VERSION 5.7 ;
BUSBITCHARS "[]" ;
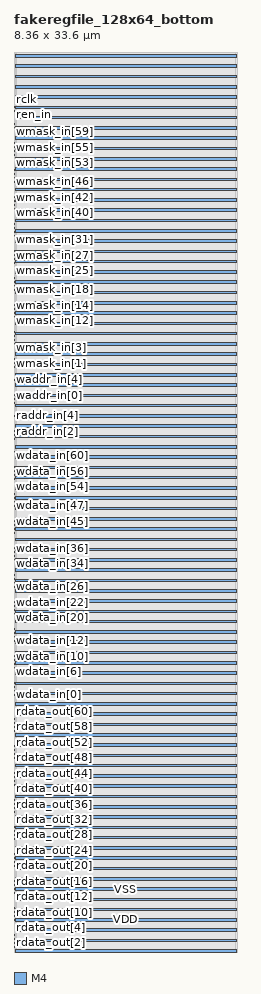
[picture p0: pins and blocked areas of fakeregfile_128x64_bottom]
MACRO fakeregfile_128x64_bottom
  FOREIGN fakeregfile_128x64_bottom 0 0 ;
  SYMMETRY X Y R90 ;
  SIZE 8.360 BY 33.600 ;
  CLASS BLOCK ;
  PIN rdata_out[0]
    DIRECTION OUTPUT ;
    USE SIGNAL ;
    SHAPE ABUTMENT ;
    PORT
      LAYER M4 ;
      RECT 0.000 0.039 0.024 0.063 ;
    END
  END rdata_out[0]
  PIN rdata_out[1]
    DIRECTION OUTPUT ;
    USE SIGNAL ;
    SHAPE ABUTMENT ;
    PORT
      LAYER M4 ;
      RECT 0.000 0.183 0.024 0.207 ;
    END
  END rdata_out[1]
  PIN rdata_out[2]
    DIRECTION OUTPUT ;
    USE SIGNAL ;
    SHAPE ABUTMENT ;
    PORT
      LAYER M4 ;
      RECT 0.000 0.327 0.024 0.351 ;
    END
  END rdata_out[2]
  PIN rdata_out[3]
    DIRECTION OUTPUT ;
    USE SIGNAL ;
    SHAPE ABUTMENT ;
    PORT
      LAYER M4 ;
      RECT 0.000 0.471 0.024 0.495 ;
    END
  END rdata_out[3]
  PIN rdata_out[4]
    DIRECTION OUTPUT ;
    USE SIGNAL ;
    SHAPE ABUTMENT ;
    PORT
      LAYER M4 ;
      RECT 0.000 0.615 0.024 0.639 ;
    END
  END rdata_out[4]
  PIN rdata_out[5]
    DIRECTION OUTPUT ;
    USE SIGNAL ;
    SHAPE ABUTMENT ;
    PORT
      LAYER M4 ;
      RECT 0.000 0.759 0.024 0.783 ;
    END
  END rdata_out[5]
  PIN rdata_out[6]
    DIRECTION OUTPUT ;
    USE SIGNAL ;
    SHAPE ABUTMENT ;
    PORT
      LAYER M4 ;
      RECT 0.000 0.903 0.024 0.927 ;
    END
  END rdata_out[6]
  PIN rdata_out[7]
    DIRECTION OUTPUT ;
    USE SIGNAL ;
    SHAPE ABUTMENT ;
    PORT
      LAYER M4 ;
      RECT 0.000 1.047 0.024 1.071 ;
    END
  END rdata_out[7]
  PIN rdata_out[8]
    DIRECTION OUTPUT ;
    USE SIGNAL ;
    SHAPE ABUTMENT ;
    PORT
      LAYER M4 ;
      RECT 0.000 1.191 0.024 1.215 ;
    END
  END rdata_out[8]
  PIN rdata_out[9]
    DIRECTION OUTPUT ;
    USE SIGNAL ;
    SHAPE ABUTMENT ;
    PORT
      LAYER M4 ;
      RECT 0.000 1.335 0.024 1.359 ;
    END
  END rdata_out[9]
  PIN rdata_out[10]
    DIRECTION OUTPUT ;
    USE SIGNAL ;
    SHAPE ABUTMENT ;
    PORT
      LAYER M4 ;
      RECT 0.000 1.479 0.024 1.503 ;
    END
  END rdata_out[10]
  PIN rdata_out[11]
    DIRECTION OUTPUT ;
    USE SIGNAL ;
    SHAPE ABUTMENT ;
    PORT
      LAYER M4 ;
      RECT 0.000 1.623 0.024 1.647 ;
    END
  END rdata_out[11]
  PIN rdata_out[12]
    DIRECTION OUTPUT ;
    USE SIGNAL ;
    SHAPE ABUTMENT ;
    PORT
      LAYER M4 ;
      RECT 0.000 1.767 0.024 1.791 ;
    END
  END rdata_out[12]
  PIN rdata_out[13]
    DIRECTION OUTPUT ;
    USE SIGNAL ;
    SHAPE ABUTMENT ;
    PORT
      LAYER M4 ;
      RECT 0.000 1.911 0.024 1.935 ;
    END
  END rdata_out[13]
  PIN rdata_out[14]
    DIRECTION OUTPUT ;
    USE SIGNAL ;
    SHAPE ABUTMENT ;
    PORT
      LAYER M4 ;
      RECT 0.000 2.055 0.024 2.079 ;
    END
  END rdata_out[14]
  PIN rdata_out[15]
    DIRECTION OUTPUT ;
    USE SIGNAL ;
    SHAPE ABUTMENT ;
    PORT
      LAYER M4 ;
      RECT 0.000 2.199 0.024 2.223 ;
    END
  END rdata_out[15]
  PIN rdata_out[16]
    DIRECTION OUTPUT ;
    USE SIGNAL ;
    SHAPE ABUTMENT ;
    PORT
      LAYER M4 ;
      RECT 0.000 2.343 0.024 2.367 ;
    END
  END rdata_out[16]
  PIN rdata_out[17]
    DIRECTION OUTPUT ;
    USE SIGNAL ;
    SHAPE ABUTMENT ;
    PORT
      LAYER M4 ;
      RECT 0.000 2.487 0.024 2.511 ;
    END
  END rdata_out[17]
  PIN rdata_out[18]
    DIRECTION OUTPUT ;
    USE SIGNAL ;
    SHAPE ABUTMENT ;
    PORT
      LAYER M4 ;
      RECT 0.000 2.631 0.024 2.655 ;
    END
  END rdata_out[18]
  PIN rdata_out[19]
    DIRECTION OUTPUT ;
    USE SIGNAL ;
    SHAPE ABUTMENT ;
    PORT
      LAYER M4 ;
      RECT 0.000 2.775 0.024 2.799 ;
    END
  END rdata_out[19]
  PIN rdata_out[20]
    DIRECTION OUTPUT ;
    USE SIGNAL ;
    SHAPE ABUTMENT ;
    PORT
      LAYER M4 ;
      RECT 0.000 2.919 0.024 2.943 ;
    END
  END rdata_out[20]
  PIN rdata_out[21]
    DIRECTION OUTPUT ;
    USE SIGNAL ;
    SHAPE ABUTMENT ;
    PORT
      LAYER M4 ;
      RECT 0.000 3.063 0.024 3.087 ;
    END
  END rdata_out[21]
  PIN rdata_out[22]
    DIRECTION OUTPUT ;
    USE SIGNAL ;
    SHAPE ABUTMENT ;
    PORT
      LAYER M4 ;
      RECT 0.000 3.207 0.024 3.231 ;
    END
  END rdata_out[22]
  PIN rdata_out[23]
    DIRECTION OUTPUT ;
    USE SIGNAL ;
    SHAPE ABUTMENT ;
    PORT
      LAYER M4 ;
      RECT 0.000 3.351 0.024 3.375 ;
    END
  END rdata_out[23]
  PIN rdata_out[24]
    DIRECTION OUTPUT ;
    USE SIGNAL ;
    SHAPE ABUTMENT ;
    PORT
      LAYER M4 ;
      RECT 0.000 3.495 0.024 3.519 ;
    END
  END rdata_out[24]
  PIN rdata_out[25]
    DIRECTION OUTPUT ;
    USE SIGNAL ;
    SHAPE ABUTMENT ;
    PORT
      LAYER M4 ;
      RECT 0.000 3.639 0.024 3.663 ;
    END
  END rdata_out[25]
  PIN rdata_out[26]
    DIRECTION OUTPUT ;
    USE SIGNAL ;
    SHAPE ABUTMENT ;
    PORT
      LAYER M4 ;
      RECT 0.000 3.783 0.024 3.807 ;
    END
  END rdata_out[26]
  PIN rdata_out[27]
    DIRECTION OUTPUT ;
    USE SIGNAL ;
    SHAPE ABUTMENT ;
    PORT
      LAYER M4 ;
      RECT 0.000 3.927 0.024 3.951 ;
    END
  END rdata_out[27]
  PIN rdata_out[28]
    DIRECTION OUTPUT ;
    USE SIGNAL ;
    SHAPE ABUTMENT ;
    PORT
      LAYER M4 ;
      RECT 0.000 4.071 0.024 4.095 ;
    END
  END rdata_out[28]
  PIN rdata_out[29]
    DIRECTION OUTPUT ;
    USE SIGNAL ;
    SHAPE ABUTMENT ;
    PORT
      LAYER M4 ;
      RECT 0.000 4.215 0.024 4.239 ;
    END
  END rdata_out[29]
  PIN rdata_out[30]
    DIRECTION OUTPUT ;
    USE SIGNAL ;
    SHAPE ABUTMENT ;
    PORT
      LAYER M4 ;
      RECT 0.000 4.359 0.024 4.383 ;
    END
  END rdata_out[30]
  PIN rdata_out[31]
    DIRECTION OUTPUT ;
    USE SIGNAL ;
    SHAPE ABUTMENT ;
    PORT
      LAYER M4 ;
      RECT 0.000 4.503 0.024 4.527 ;
    END
  END rdata_out[31]
  PIN rdata_out[32]
    DIRECTION OUTPUT ;
    USE SIGNAL ;
    SHAPE ABUTMENT ;
    PORT
      LAYER M4 ;
      RECT 0.000 4.647 0.024 4.671 ;
    END
  END rdata_out[32]
  PIN rdata_out[33]
    DIRECTION OUTPUT ;
    USE SIGNAL ;
    SHAPE ABUTMENT ;
    PORT
      LAYER M4 ;
      RECT 0.000 4.791 0.024 4.815 ;
    END
  END rdata_out[33]
  PIN rdata_out[34]
    DIRECTION OUTPUT ;
    USE SIGNAL ;
    SHAPE ABUTMENT ;
    PORT
      LAYER M4 ;
      RECT 0.000 4.935 0.024 4.959 ;
    END
  END rdata_out[34]
  PIN rdata_out[35]
    DIRECTION OUTPUT ;
    USE SIGNAL ;
    SHAPE ABUTMENT ;
    PORT
      LAYER M4 ;
      RECT 0.000 5.079 0.024 5.103 ;
    END
  END rdata_out[35]
  PIN rdata_out[36]
    DIRECTION OUTPUT ;
    USE SIGNAL ;
    SHAPE ABUTMENT ;
    PORT
      LAYER M4 ;
      RECT 0.000 5.223 0.024 5.247 ;
    END
  END rdata_out[36]
  PIN rdata_out[37]
    DIRECTION OUTPUT ;
    USE SIGNAL ;
    SHAPE ABUTMENT ;
    PORT
      LAYER M4 ;
      RECT 0.000 5.367 0.024 5.391 ;
    END
  END rdata_out[37]
  PIN rdata_out[38]
    DIRECTION OUTPUT ;
    USE SIGNAL ;
    SHAPE ABUTMENT ;
    PORT
      LAYER M4 ;
      RECT 0.000 5.511 0.024 5.535 ;
    END
  END rdata_out[38]
  PIN rdata_out[39]
    DIRECTION OUTPUT ;
    USE SIGNAL ;
    SHAPE ABUTMENT ;
    PORT
      LAYER M4 ;
      RECT 0.000 5.655 0.024 5.679 ;
    END
  END rdata_out[39]
  PIN rdata_out[40]
    DIRECTION OUTPUT ;
    USE SIGNAL ;
    SHAPE ABUTMENT ;
    PORT
      LAYER M4 ;
      RECT 0.000 5.799 0.024 5.823 ;
    END
  END rdata_out[40]
  PIN rdata_out[41]
    DIRECTION OUTPUT ;
    USE SIGNAL ;
    SHAPE ABUTMENT ;
    PORT
      LAYER M4 ;
      RECT 0.000 5.943 0.024 5.967 ;
    END
  END rdata_out[41]
  PIN rdata_out[42]
    DIRECTION OUTPUT ;
    USE SIGNAL ;
    SHAPE ABUTMENT ;
    PORT
      LAYER M4 ;
      RECT 0.000 6.087 0.024 6.111 ;
    END
  END rdata_out[42]
  PIN rdata_out[43]
    DIRECTION OUTPUT ;
    USE SIGNAL ;
    SHAPE ABUTMENT ;
    PORT
      LAYER M4 ;
      RECT 0.000 6.231 0.024 6.255 ;
    END
  END rdata_out[43]
  PIN rdata_out[44]
    DIRECTION OUTPUT ;
    USE SIGNAL ;
    SHAPE ABUTMENT ;
    PORT
      LAYER M4 ;
      RECT 0.000 6.375 0.024 6.399 ;
    END
  END rdata_out[44]
  PIN rdata_out[45]
    DIRECTION OUTPUT ;
    USE SIGNAL ;
    SHAPE ABUTMENT ;
    PORT
      LAYER M4 ;
      RECT 0.000 6.519 0.024 6.543 ;
    END
  END rdata_out[45]
  PIN rdata_out[46]
    DIRECTION OUTPUT ;
    USE SIGNAL ;
    SHAPE ABUTMENT ;
    PORT
      LAYER M4 ;
      RECT 0.000 6.663 0.024 6.687 ;
    END
  END rdata_out[46]
  PIN rdata_out[47]
    DIRECTION OUTPUT ;
    USE SIGNAL ;
    SHAPE ABUTMENT ;
    PORT
      LAYER M4 ;
      RECT 0.000 6.807 0.024 6.831 ;
    END
  END rdata_out[47]
  PIN rdata_out[48]
    DIRECTION OUTPUT ;
    USE SIGNAL ;
    SHAPE ABUTMENT ;
    PORT
      LAYER M4 ;
      RECT 0.000 6.951 0.024 6.975 ;
    END
  END rdata_out[48]
  PIN rdata_out[49]
    DIRECTION OUTPUT ;
    USE SIGNAL ;
    SHAPE ABUTMENT ;
    PORT
      LAYER M4 ;
      RECT 0.000 7.095 0.024 7.119 ;
    END
  END rdata_out[49]
  PIN rdata_out[50]
    DIRECTION OUTPUT ;
    USE SIGNAL ;
    SHAPE ABUTMENT ;
    PORT
      LAYER M4 ;
      RECT 0.000 7.239 0.024 7.263 ;
    END
  END rdata_out[50]
  PIN rdata_out[51]
    DIRECTION OUTPUT ;
    USE SIGNAL ;
    SHAPE ABUTMENT ;
    PORT
      LAYER M4 ;
      RECT 0.000 7.383 0.024 7.407 ;
    END
  END rdata_out[51]
  PIN rdata_out[52]
    DIRECTION OUTPUT ;
    USE SIGNAL ;
    SHAPE ABUTMENT ;
    PORT
      LAYER M4 ;
      RECT 0.000 7.527 0.024 7.551 ;
    END
  END rdata_out[52]
  PIN rdata_out[53]
    DIRECTION OUTPUT ;
    USE SIGNAL ;
    SHAPE ABUTMENT ;
    PORT
      LAYER M4 ;
      RECT 0.000 7.671 0.024 7.695 ;
    END
  END rdata_out[53]
  PIN rdata_out[54]
    DIRECTION OUTPUT ;
    USE SIGNAL ;
    SHAPE ABUTMENT ;
    PORT
      LAYER M4 ;
      RECT 0.000 7.815 0.024 7.839 ;
    END
  END rdata_out[54]
  PIN rdata_out[55]
    DIRECTION OUTPUT ;
    USE SIGNAL ;
    SHAPE ABUTMENT ;
    PORT
      LAYER M4 ;
      RECT 0.000 7.959 0.024 7.983 ;
    END
  END rdata_out[55]
  PIN rdata_out[56]
    DIRECTION OUTPUT ;
    USE SIGNAL ;
    SHAPE ABUTMENT ;
    PORT
      LAYER M4 ;
      RECT 0.000 8.103 0.024 8.127 ;
    END
  END rdata_out[56]
  PIN rdata_out[57]
    DIRECTION OUTPUT ;
    USE SIGNAL ;
    SHAPE ABUTMENT ;
    PORT
      LAYER M4 ;
      RECT 0.000 8.247 0.024 8.271 ;
    END
  END rdata_out[57]
  PIN rdata_out[58]
    DIRECTION OUTPUT ;
    USE SIGNAL ;
    SHAPE ABUTMENT ;
    PORT
      LAYER M4 ;
      RECT 0.000 8.391 0.024 8.415 ;
    END
  END rdata_out[58]
  PIN rdata_out[59]
    DIRECTION OUTPUT ;
    USE SIGNAL ;
    SHAPE ABUTMENT ;
    PORT
      LAYER M4 ;
      RECT 0.000 8.535 0.024 8.559 ;
    END
  END rdata_out[59]
  PIN rdata_out[60]
    DIRECTION OUTPUT ;
    USE SIGNAL ;
    SHAPE ABUTMENT ;
    PORT
      LAYER M4 ;
      RECT 0.000 8.679 0.024 8.703 ;
    END
  END rdata_out[60]
  PIN rdata_out[61]
    DIRECTION OUTPUT ;
    USE SIGNAL ;
    SHAPE ABUTMENT ;
    PORT
      LAYER M4 ;
      RECT 0.000 8.823 0.024 8.847 ;
    END
  END rdata_out[61]
  PIN rdata_out[62]
    DIRECTION OUTPUT ;
    USE SIGNAL ;
    SHAPE ABUTMENT ;
    PORT
      LAYER M4 ;
      RECT 0.000 8.967 0.024 8.991 ;
    END
  END rdata_out[62]
  PIN rdata_out[63]
    DIRECTION OUTPUT ;
    USE SIGNAL ;
    SHAPE ABUTMENT ;
    PORT
      LAYER M4 ;
      RECT 0.000 9.111 0.024 9.135 ;
    END
  END rdata_out[63]
  PIN wdata_in[0]
    DIRECTION INPUT ;
    USE SIGNAL ;
    SHAPE ABUTMENT ;
    PORT
      LAYER M4 ;
      RECT 0.000 9.591 0.024 9.615 ;
    END
  END wdata_in[0]
  PIN wdata_in[1]
    DIRECTION INPUT ;
    USE SIGNAL ;
    SHAPE ABUTMENT ;
    PORT
      LAYER M4 ;
      RECT 0.000 9.735 0.024 9.759 ;
    END
  END wdata_in[1]
  PIN wdata_in[2]
    DIRECTION INPUT ;
    USE SIGNAL ;
    SHAPE ABUTMENT ;
    PORT
      LAYER M4 ;
      RECT 0.000 9.879 0.024 9.903 ;
    END
  END wdata_in[2]
  PIN wdata_in[3]
    DIRECTION INPUT ;
    USE SIGNAL ;
    SHAPE ABUTMENT ;
    PORT
      LAYER M4 ;
      RECT 0.000 10.023 0.024 10.047 ;
    END
  END wdata_in[3]
  PIN wdata_in[4]
    DIRECTION INPUT ;
    USE SIGNAL ;
    SHAPE ABUTMENT ;
    PORT
      LAYER M4 ;
      RECT 0.000 10.167 0.024 10.191 ;
    END
  END wdata_in[4]
  PIN wdata_in[5]
    DIRECTION INPUT ;
    USE SIGNAL ;
    SHAPE ABUTMENT ;
    PORT
      LAYER M4 ;
      RECT 0.000 10.311 0.024 10.335 ;
    END
  END wdata_in[5]
  PIN wdata_in[6]
    DIRECTION INPUT ;
    USE SIGNAL ;
    SHAPE ABUTMENT ;
    PORT
      LAYER M4 ;
      RECT 0.000 10.455 0.024 10.479 ;
    END
  END wdata_in[6]
  PIN wdata_in[7]
    DIRECTION INPUT ;
    USE SIGNAL ;
    SHAPE ABUTMENT ;
    PORT
      LAYER M4 ;
      RECT 0.000 10.599 0.024 10.623 ;
    END
  END wdata_in[7]
  PIN wdata_in[8]
    DIRECTION INPUT ;
    USE SIGNAL ;
    SHAPE ABUTMENT ;
    PORT
      LAYER M4 ;
      RECT 0.000 10.743 0.024 10.767 ;
    END
  END wdata_in[8]
  PIN wdata_in[9]
    DIRECTION INPUT ;
    USE SIGNAL ;
    SHAPE ABUTMENT ;
    PORT
      LAYER M4 ;
      RECT 0.000 10.887 0.024 10.911 ;
    END
  END wdata_in[9]
  PIN wdata_in[10]
    DIRECTION INPUT ;
    USE SIGNAL ;
    SHAPE ABUTMENT ;
    PORT
      LAYER M4 ;
      RECT 0.000 11.031 0.024 11.055 ;
    END
  END wdata_in[10]
  PIN wdata_in[11]
    DIRECTION INPUT ;
    USE SIGNAL ;
    SHAPE ABUTMENT ;
    PORT
      LAYER M4 ;
      RECT 0.000 11.175 0.024 11.199 ;
    END
  END wdata_in[11]
  PIN wdata_in[12]
    DIRECTION INPUT ;
    USE SIGNAL ;
    SHAPE ABUTMENT ;
    PORT
      LAYER M4 ;
      RECT 0.000 11.319 0.024 11.343 ;
    END
  END wdata_in[12]
  PIN wdata_in[13]
    DIRECTION INPUT ;
    USE SIGNAL ;
    SHAPE ABUTMENT ;
    PORT
      LAYER M4 ;
      RECT 0.000 11.463 0.024 11.487 ;
    END
  END wdata_in[13]
  PIN wdata_in[14]
    DIRECTION INPUT ;
    USE SIGNAL ;
    SHAPE ABUTMENT ;
    PORT
      LAYER M4 ;
      RECT 0.000 11.607 0.024 11.631 ;
    END
  END wdata_in[14]
  PIN wdata_in[15]
    DIRECTION INPUT ;
    USE SIGNAL ;
    SHAPE ABUTMENT ;
    PORT
      LAYER M4 ;
      RECT 0.000 11.751 0.024 11.775 ;
    END
  END wdata_in[15]
  PIN wdata_in[16]
    DIRECTION INPUT ;
    USE SIGNAL ;
    SHAPE ABUTMENT ;
    PORT
      LAYER M4 ;
      RECT 0.000 11.895 0.024 11.919 ;
    END
  END wdata_in[16]
  PIN wdata_in[17]
    DIRECTION INPUT ;
    USE SIGNAL ;
    SHAPE ABUTMENT ;
    PORT
      LAYER M4 ;
      RECT 0.000 12.039 0.024 12.063 ;
    END
  END wdata_in[17]
  PIN wdata_in[18]
    DIRECTION INPUT ;
    USE SIGNAL ;
    SHAPE ABUTMENT ;
    PORT
      LAYER M4 ;
      RECT 0.000 12.183 0.024 12.207 ;
    END
  END wdata_in[18]
  PIN wdata_in[19]
    DIRECTION INPUT ;
    USE SIGNAL ;
    SHAPE ABUTMENT ;
    PORT
      LAYER M4 ;
      RECT 0.000 12.327 0.024 12.351 ;
    END
  END wdata_in[19]
  PIN wdata_in[20]
    DIRECTION INPUT ;
    USE SIGNAL ;
    SHAPE ABUTMENT ;
    PORT
      LAYER M4 ;
      RECT 0.000 12.471 0.024 12.495 ;
    END
  END wdata_in[20]
  PIN wdata_in[21]
    DIRECTION INPUT ;
    USE SIGNAL ;
    SHAPE ABUTMENT ;
    PORT
      LAYER M4 ;
      RECT 0.000 12.615 0.024 12.639 ;
    END
  END wdata_in[21]
  PIN wdata_in[22]
    DIRECTION INPUT ;
    USE SIGNAL ;
    SHAPE ABUTMENT ;
    PORT
      LAYER M4 ;
      RECT 0.000 12.759 0.024 12.783 ;
    END
  END wdata_in[22]
  PIN wdata_in[23]
    DIRECTION INPUT ;
    USE SIGNAL ;
    SHAPE ABUTMENT ;
    PORT
      LAYER M4 ;
      RECT 0.000 12.903 0.024 12.927 ;
    END
  END wdata_in[23]
  PIN wdata_in[24]
    DIRECTION INPUT ;
    USE SIGNAL ;
    SHAPE ABUTMENT ;
    PORT
      LAYER M4 ;
      RECT 0.000 13.047 0.024 13.071 ;
    END
  END wdata_in[24]
  PIN wdata_in[25]
    DIRECTION INPUT ;
    USE SIGNAL ;
    SHAPE ABUTMENT ;
    PORT
      LAYER M4 ;
      RECT 0.000 13.191 0.024 13.215 ;
    END
  END wdata_in[25]
  PIN wdata_in[26]
    DIRECTION INPUT ;
    USE SIGNAL ;
    SHAPE ABUTMENT ;
    PORT
      LAYER M4 ;
      RECT 0.000 13.335 0.024 13.359 ;
    END
  END wdata_in[26]
  PIN wdata_in[27]
    DIRECTION INPUT ;
    USE SIGNAL ;
    SHAPE ABUTMENT ;
    PORT
      LAYER M4 ;
      RECT 0.000 13.479 0.024 13.503 ;
    END
  END wdata_in[27]
  PIN wdata_in[28]
    DIRECTION INPUT ;
    USE SIGNAL ;
    SHAPE ABUTMENT ;
    PORT
      LAYER M4 ;
      RECT 0.000 13.623 0.024 13.647 ;
    END
  END wdata_in[28]
  PIN wdata_in[29]
    DIRECTION INPUT ;
    USE SIGNAL ;
    SHAPE ABUTMENT ;
    PORT
      LAYER M4 ;
      RECT 0.000 13.767 0.024 13.791 ;
    END
  END wdata_in[29]
  PIN wdata_in[30]
    DIRECTION INPUT ;
    USE SIGNAL ;
    SHAPE ABUTMENT ;
    PORT
      LAYER M4 ;
      RECT 0.000 13.911 0.024 13.935 ;
    END
  END wdata_in[30]
  PIN wdata_in[31]
    DIRECTION INPUT ;
    USE SIGNAL ;
    SHAPE ABUTMENT ;
    PORT
      LAYER M4 ;
      RECT 0.000 14.055 0.024 14.079 ;
    END
  END wdata_in[31]
  PIN wdata_in[32]
    DIRECTION INPUT ;
    USE SIGNAL ;
    SHAPE ABUTMENT ;
    PORT
      LAYER M4 ;
      RECT 0.000 14.199 0.024 14.223 ;
    END
  END wdata_in[32]
  PIN wdata_in[33]
    DIRECTION INPUT ;
    USE SIGNAL ;
    SHAPE ABUTMENT ;
    PORT
      LAYER M4 ;
      RECT 0.000 14.343 0.024 14.367 ;
    END
  END wdata_in[33]
  PIN wdata_in[34]
    DIRECTION INPUT ;
    USE SIGNAL ;
    SHAPE ABUTMENT ;
    PORT
      LAYER M4 ;
      RECT 0.000 14.487 0.024 14.511 ;
    END
  END wdata_in[34]
  PIN wdata_in[35]
    DIRECTION INPUT ;
    USE SIGNAL ;
    SHAPE ABUTMENT ;
    PORT
      LAYER M4 ;
      RECT 0.000 14.631 0.024 14.655 ;
    END
  END wdata_in[35]
  PIN wdata_in[36]
    DIRECTION INPUT ;
    USE SIGNAL ;
    SHAPE ABUTMENT ;
    PORT
      LAYER M4 ;
      RECT 0.000 14.775 0.024 14.799 ;
    END
  END wdata_in[36]
  PIN wdata_in[37]
    DIRECTION INPUT ;
    USE SIGNAL ;
    SHAPE ABUTMENT ;
    PORT
      LAYER M4 ;
      RECT 0.000 14.919 0.024 14.943 ;
    END
  END wdata_in[37]
  PIN wdata_in[38]
    DIRECTION INPUT ;
    USE SIGNAL ;
    SHAPE ABUTMENT ;
    PORT
      LAYER M4 ;
      RECT 0.000 15.063 0.024 15.087 ;
    END
  END wdata_in[38]
  PIN wdata_in[39]
    DIRECTION INPUT ;
    USE SIGNAL ;
    SHAPE ABUTMENT ;
    PORT
      LAYER M4 ;
      RECT 0.000 15.207 0.024 15.231 ;
    END
  END wdata_in[39]
  PIN wdata_in[40]
    DIRECTION INPUT ;
    USE SIGNAL ;
    SHAPE ABUTMENT ;
    PORT
      LAYER M4 ;
      RECT 0.000 15.351 0.024 15.375 ;
    END
  END wdata_in[40]
  PIN wdata_in[41]
    DIRECTION INPUT ;
    USE SIGNAL ;
    SHAPE ABUTMENT ;
    PORT
      LAYER M4 ;
      RECT 0.000 15.495 0.024 15.519 ;
    END
  END wdata_in[41]
  PIN wdata_in[42]
    DIRECTION INPUT ;
    USE SIGNAL ;
    SHAPE ABUTMENT ;
    PORT
      LAYER M4 ;
      RECT 0.000 15.639 0.024 15.663 ;
    END
  END wdata_in[42]
  PIN wdata_in[43]
    DIRECTION INPUT ;
    USE SIGNAL ;
    SHAPE ABUTMENT ;
    PORT
      LAYER M4 ;
      RECT 0.000 15.783 0.024 15.807 ;
    END
  END wdata_in[43]
  PIN wdata_in[44]
    DIRECTION INPUT ;
    USE SIGNAL ;
    SHAPE ABUTMENT ;
    PORT
      LAYER M4 ;
      RECT 0.000 15.927 0.024 15.951 ;
    END
  END wdata_in[44]
  PIN wdata_in[45]
    DIRECTION INPUT ;
    USE SIGNAL ;
    SHAPE ABUTMENT ;
    PORT
      LAYER M4 ;
      RECT 0.000 16.071 0.024 16.095 ;
    END
  END wdata_in[45]
  PIN wdata_in[46]
    DIRECTION INPUT ;
    USE SIGNAL ;
    SHAPE ABUTMENT ;
    PORT
      LAYER M4 ;
      RECT 0.000 16.215 0.024 16.239 ;
    END
  END wdata_in[46]
  PIN wdata_in[47]
    DIRECTION INPUT ;
    USE SIGNAL ;
    SHAPE ABUTMENT ;
    PORT
      LAYER M4 ;
      RECT 0.000 16.359 0.024 16.383 ;
    END
  END wdata_in[47]
  PIN wdata_in[48]
    DIRECTION INPUT ;
    USE SIGNAL ;
    SHAPE ABUTMENT ;
    PORT
      LAYER M4 ;
      RECT 0.000 16.503 0.024 16.527 ;
    END
  END wdata_in[48]
  PIN wdata_in[49]
    DIRECTION INPUT ;
    USE SIGNAL ;
    SHAPE ABUTMENT ;
    PORT
      LAYER M4 ;
      RECT 0.000 16.647 0.024 16.671 ;
    END
  END wdata_in[49]
  PIN wdata_in[50]
    DIRECTION INPUT ;
    USE SIGNAL ;
    SHAPE ABUTMENT ;
    PORT
      LAYER M4 ;
      RECT 0.000 16.791 0.024 16.815 ;
    END
  END wdata_in[50]
  PIN wdata_in[51]
    DIRECTION INPUT ;
    USE SIGNAL ;
    SHAPE ABUTMENT ;
    PORT
      LAYER M4 ;
      RECT 0.000 16.935 0.024 16.959 ;
    END
  END wdata_in[51]
  PIN wdata_in[52]
    DIRECTION INPUT ;
    USE SIGNAL ;
    SHAPE ABUTMENT ;
    PORT
      LAYER M4 ;
      RECT 0.000 17.079 0.024 17.103 ;
    END
  END wdata_in[52]
  PIN wdata_in[53]
    DIRECTION INPUT ;
    USE SIGNAL ;
    SHAPE ABUTMENT ;
    PORT
      LAYER M4 ;
      RECT 0.000 17.223 0.024 17.247 ;
    END
  END wdata_in[53]
  PIN wdata_in[54]
    DIRECTION INPUT ;
    USE SIGNAL ;
    SHAPE ABUTMENT ;
    PORT
      LAYER M4 ;
      RECT 0.000 17.367 0.024 17.391 ;
    END
  END wdata_in[54]
  PIN wdata_in[55]
    DIRECTION INPUT ;
    USE SIGNAL ;
    SHAPE ABUTMENT ;
    PORT
      LAYER M4 ;
      RECT 0.000 17.511 0.024 17.535 ;
    END
  END wdata_in[55]
  PIN wdata_in[56]
    DIRECTION INPUT ;
    USE SIGNAL ;
    SHAPE ABUTMENT ;
    PORT
      LAYER M4 ;
      RECT 0.000 17.655 0.024 17.679 ;
    END
  END wdata_in[56]
  PIN wdata_in[57]
    DIRECTION INPUT ;
    USE SIGNAL ;
    SHAPE ABUTMENT ;
    PORT
      LAYER M4 ;
      RECT 0.000 17.799 0.024 17.823 ;
    END
  END wdata_in[57]
  PIN wdata_in[58]
    DIRECTION INPUT ;
    USE SIGNAL ;
    SHAPE ABUTMENT ;
    PORT
      LAYER M4 ;
      RECT 0.000 17.943 0.024 17.967 ;
    END
  END wdata_in[58]
  PIN wdata_in[59]
    DIRECTION INPUT ;
    USE SIGNAL ;
    SHAPE ABUTMENT ;
    PORT
      LAYER M4 ;
      RECT 0.000 18.087 0.024 18.111 ;
    END
  END wdata_in[59]
  PIN wdata_in[60]
    DIRECTION INPUT ;
    USE SIGNAL ;
    SHAPE ABUTMENT ;
    PORT
      LAYER M4 ;
      RECT 0.000 18.231 0.024 18.255 ;
    END
  END wdata_in[60]
  PIN wdata_in[61]
    DIRECTION INPUT ;
    USE SIGNAL ;
    SHAPE ABUTMENT ;
    PORT
      LAYER M4 ;
      RECT 0.000 18.375 0.024 18.399 ;
    END
  END wdata_in[61]
  PIN wdata_in[62]
    DIRECTION INPUT ;
    USE SIGNAL ;
    SHAPE ABUTMENT ;
    PORT
      LAYER M4 ;
      RECT 0.000 18.519 0.024 18.543 ;
    END
  END wdata_in[62]
  PIN wdata_in[63]
    DIRECTION INPUT ;
    USE SIGNAL ;
    SHAPE ABUTMENT ;
    PORT
      LAYER M4 ;
      RECT 0.000 18.663 0.024 18.687 ;
    END
  END wdata_in[63]
  PIN raddr_in[0]
    DIRECTION INPUT ;
    USE SIGNAL ;
    SHAPE ABUTMENT ;
    PORT
      LAYER M4 ;
      RECT 0.000 19.143 0.024 19.167 ;
    END
  END raddr_in[0]
  PIN raddr_in[1]
    DIRECTION INPUT ;
    USE SIGNAL ;
    SHAPE ABUTMENT ;
    PORT
      LAYER M4 ;
      RECT 0.000 19.287 0.024 19.311 ;
    END
  END raddr_in[1]
  PIN raddr_in[2]
    DIRECTION INPUT ;
    USE SIGNAL ;
    SHAPE ABUTMENT ;
    PORT
      LAYER M4 ;
      RECT 0.000 19.431 0.024 19.455 ;
    END
  END raddr_in[2]
  PIN raddr_in[3]
    DIRECTION INPUT ;
    USE SIGNAL ;
    SHAPE ABUTMENT ;
    PORT
      LAYER M4 ;
      RECT 0.000 19.575 0.024 19.599 ;
    END
  END raddr_in[3]
  PIN raddr_in[4]
    DIRECTION INPUT ;
    USE SIGNAL ;
    SHAPE ABUTMENT ;
    PORT
      LAYER M4 ;
      RECT 0.000 19.719 0.024 19.743 ;
    END
  END raddr_in[4]
  PIN raddr_in[5]
    DIRECTION INPUT ;
    USE SIGNAL ;
    SHAPE ABUTMENT ;
    PORT
      LAYER M4 ;
      RECT 0.000 19.863 0.024 19.887 ;
    END
  END raddr_in[5]
  PIN raddr_in[6]
    DIRECTION INPUT ;
    USE SIGNAL ;
    SHAPE ABUTMENT ;
    PORT
      LAYER M4 ;
      RECT 0.000 20.007 0.024 20.031 ;
    END
  END raddr_in[6]
  PIN waddr_in[0]
    DIRECTION INPUT ;
    USE SIGNAL ;
    SHAPE ABUTMENT ;
    PORT
      LAYER M4 ;
      RECT 0.000 20.487 0.024 20.511 ;
    END
  END waddr_in[0]
  PIN waddr_in[1]
    DIRECTION INPUT ;
    USE SIGNAL ;
    SHAPE ABUTMENT ;
    PORT
      LAYER M4 ;
      RECT 0.000 20.631 0.024 20.655 ;
    END
  END waddr_in[1]
  PIN waddr_in[2]
    DIRECTION INPUT ;
    USE SIGNAL ;
    SHAPE ABUTMENT ;
    PORT
      LAYER M4 ;
      RECT 0.000 20.775 0.024 20.799 ;
    END
  END waddr_in[2]
  PIN waddr_in[3]
    DIRECTION INPUT ;
    USE SIGNAL ;
    SHAPE ABUTMENT ;
    PORT
      LAYER M4 ;
      RECT 0.000 20.919 0.024 20.943 ;
    END
  END waddr_in[3]
  PIN waddr_in[4]
    DIRECTION INPUT ;
    USE SIGNAL ;
    SHAPE ABUTMENT ;
    PORT
      LAYER M4 ;
      RECT 0.000 21.063 0.024 21.087 ;
    END
  END waddr_in[4]
  PIN waddr_in[5]
    DIRECTION INPUT ;
    USE SIGNAL ;
    SHAPE ABUTMENT ;
    PORT
      LAYER M4 ;
      RECT 0.000 21.207 0.024 21.231 ;
    END
  END waddr_in[5]
  PIN waddr_in[6]
    DIRECTION INPUT ;
    USE SIGNAL ;
    SHAPE ABUTMENT ;
    PORT
      LAYER M4 ;
      RECT 0.000 21.351 0.024 21.375 ;
    END
  END waddr_in[6]
  PIN wmask_in[0]
    DIRECTION INPUT ;
    USE SIGNAL ;
    SHAPE ABUTMENT ;
    PORT
      LAYER M4 ;
      RECT 0.000 21.831 0.024 21.855 ;
    END
  END wmask_in[0]
  PIN wmask_in[1]
    DIRECTION INPUT ;
    USE SIGNAL ;
    SHAPE ABUTMENT ;
    PORT
      LAYER M4 ;
      RECT 0.000 21.975 0.024 21.999 ;
    END
  END wmask_in[1]
  PIN wmask_in[2]
    DIRECTION INPUT ;
    USE SIGNAL ;
    SHAPE ABUTMENT ;
    PORT
      LAYER M4 ;
      RECT 0.000 22.119 0.024 22.143 ;
    END
  END wmask_in[2]
  PIN wmask_in[3]
    DIRECTION INPUT ;
    USE SIGNAL ;
    SHAPE ABUTMENT ;
    PORT
      LAYER M4 ;
      RECT 0.000 22.263 0.024 22.287 ;
    END
  END wmask_in[3]
  PIN wmask_in[4]
    DIRECTION INPUT ;
    USE SIGNAL ;
    SHAPE ABUTMENT ;
    PORT
      LAYER M4 ;
      RECT 0.000 22.407 0.024 22.431 ;
    END
  END wmask_in[4]
  PIN wmask_in[5]
    DIRECTION INPUT ;
    USE SIGNAL ;
    SHAPE ABUTMENT ;
    PORT
      LAYER M4 ;
      RECT 0.000 22.551 0.024 22.575 ;
    END
  END wmask_in[5]
  PIN wmask_in[6]
    DIRECTION INPUT ;
    USE SIGNAL ;
    SHAPE ABUTMENT ;
    PORT
      LAYER M4 ;
      RECT 0.000 22.695 0.024 22.719 ;
    END
  END wmask_in[6]
  PIN wmask_in[7]
    DIRECTION INPUT ;
    USE SIGNAL ;
    SHAPE ABUTMENT ;
    PORT
      LAYER M4 ;
      RECT 0.000 22.839 0.024 22.863 ;
    END
  END wmask_in[7]
  PIN wmask_in[8]
    DIRECTION INPUT ;
    USE SIGNAL ;
    SHAPE ABUTMENT ;
    PORT
      LAYER M4 ;
      RECT 0.000 22.983 0.024 23.007 ;
    END
  END wmask_in[8]
  PIN wmask_in[9]
    DIRECTION INPUT ;
    USE SIGNAL ;
    SHAPE ABUTMENT ;
    PORT
      LAYER M4 ;
      RECT 0.000 23.127 0.024 23.151 ;
    END
  END wmask_in[9]
  PIN wmask_in[10]
    DIRECTION INPUT ;
    USE SIGNAL ;
    SHAPE ABUTMENT ;
    PORT
      LAYER M4 ;
      RECT 0.000 23.271 0.024 23.295 ;
    END
  END wmask_in[10]
  PIN wmask_in[11]
    DIRECTION INPUT ;
    USE SIGNAL ;
    SHAPE ABUTMENT ;
    PORT
      LAYER M4 ;
      RECT 0.000 23.415 0.024 23.439 ;
    END
  END wmask_in[11]
  PIN wmask_in[12]
    DIRECTION INPUT ;
    USE SIGNAL ;
    SHAPE ABUTMENT ;
    PORT
      LAYER M4 ;
      RECT 0.000 23.559 0.024 23.583 ;
    END
  END wmask_in[12]
  PIN wmask_in[13]
    DIRECTION INPUT ;
    USE SIGNAL ;
    SHAPE ABUTMENT ;
    PORT
      LAYER M4 ;
      RECT 0.000 23.703 0.024 23.727 ;
    END
  END wmask_in[13]
  PIN wmask_in[14]
    DIRECTION INPUT ;
    USE SIGNAL ;
    SHAPE ABUTMENT ;
    PORT
      LAYER M4 ;
      RECT 0.000 23.847 0.024 23.871 ;
    END
  END wmask_in[14]
  PIN wmask_in[15]
    DIRECTION INPUT ;
    USE SIGNAL ;
    SHAPE ABUTMENT ;
    PORT
      LAYER M4 ;
      RECT 0.000 23.991 0.024 24.015 ;
    END
  END wmask_in[15]
  PIN wmask_in[16]
    DIRECTION INPUT ;
    USE SIGNAL ;
    SHAPE ABUTMENT ;
    PORT
      LAYER M4 ;
      RECT 0.000 24.135 0.024 24.159 ;
    END
  END wmask_in[16]
  PIN wmask_in[17]
    DIRECTION INPUT ;
    USE SIGNAL ;
    SHAPE ABUTMENT ;
    PORT
      LAYER M4 ;
      RECT 0.000 24.279 0.024 24.303 ;
    END
  END wmask_in[17]
  PIN wmask_in[18]
    DIRECTION INPUT ;
    USE SIGNAL ;
    SHAPE ABUTMENT ;
    PORT
      LAYER M4 ;
      RECT 0.000 24.423 0.024 24.447 ;
    END
  END wmask_in[18]
  PIN wmask_in[19]
    DIRECTION INPUT ;
    USE SIGNAL ;
    SHAPE ABUTMENT ;
    PORT
      LAYER M4 ;
      RECT 0.000 24.567 0.024 24.591 ;
    END
  END wmask_in[19]
  PIN wmask_in[20]
    DIRECTION INPUT ;
    USE SIGNAL ;
    SHAPE ABUTMENT ;
    PORT
      LAYER M4 ;
      RECT 0.000 24.711 0.024 24.735 ;
    END
  END wmask_in[20]
  PIN wmask_in[21]
    DIRECTION INPUT ;
    USE SIGNAL ;
    SHAPE ABUTMENT ;
    PORT
      LAYER M4 ;
      RECT 0.000 24.855 0.024 24.879 ;
    END
  END wmask_in[21]
  PIN wmask_in[22]
    DIRECTION INPUT ;
    USE SIGNAL ;
    SHAPE ABUTMENT ;
    PORT
      LAYER M4 ;
      RECT 0.000 24.999 0.024 25.023 ;
    END
  END wmask_in[22]
  PIN wmask_in[23]
    DIRECTION INPUT ;
    USE SIGNAL ;
    SHAPE ABUTMENT ;
    PORT
      LAYER M4 ;
      RECT 0.000 25.143 0.024 25.167 ;
    END
  END wmask_in[23]
  PIN wmask_in[24]
    DIRECTION INPUT ;
    USE SIGNAL ;
    SHAPE ABUTMENT ;
    PORT
      LAYER M4 ;
      RECT 0.000 25.287 0.024 25.311 ;
    END
  END wmask_in[24]
  PIN wmask_in[25]
    DIRECTION INPUT ;
    USE SIGNAL ;
    SHAPE ABUTMENT ;
    PORT
      LAYER M4 ;
      RECT 0.000 25.431 0.024 25.455 ;
    END
  END wmask_in[25]
  PIN wmask_in[26]
    DIRECTION INPUT ;
    USE SIGNAL ;
    SHAPE ABUTMENT ;
    PORT
      LAYER M4 ;
      RECT 0.000 25.575 0.024 25.599 ;
    END
  END wmask_in[26]
  PIN wmask_in[27]
    DIRECTION INPUT ;
    USE SIGNAL ;
    SHAPE ABUTMENT ;
    PORT
      LAYER M4 ;
      RECT 0.000 25.719 0.024 25.743 ;
    END
  END wmask_in[27]
  PIN wmask_in[28]
    DIRECTION INPUT ;
    USE SIGNAL ;
    SHAPE ABUTMENT ;
    PORT
      LAYER M4 ;
      RECT 0.000 25.863 0.024 25.887 ;
    END
  END wmask_in[28]
  PIN wmask_in[29]
    DIRECTION INPUT ;
    USE SIGNAL ;
    SHAPE ABUTMENT ;
    PORT
      LAYER M4 ;
      RECT 0.000 26.007 0.024 26.031 ;
    END
  END wmask_in[29]
  PIN wmask_in[30]
    DIRECTION INPUT ;
    USE SIGNAL ;
    SHAPE ABUTMENT ;
    PORT
      LAYER M4 ;
      RECT 0.000 26.151 0.024 26.175 ;
    END
  END wmask_in[30]
  PIN wmask_in[31]
    DIRECTION INPUT ;
    USE SIGNAL ;
    SHAPE ABUTMENT ;
    PORT
      LAYER M4 ;
      RECT 0.000 26.295 0.024 26.319 ;
    END
  END wmask_in[31]
  PIN wmask_in[32]
    DIRECTION INPUT ;
    USE SIGNAL ;
    SHAPE ABUTMENT ;
    PORT
      LAYER M4 ;
      RECT 0.000 26.439 0.024 26.463 ;
    END
  END wmask_in[32]
  PIN wmask_in[33]
    DIRECTION INPUT ;
    USE SIGNAL ;
    SHAPE ABUTMENT ;
    PORT
      LAYER M4 ;
      RECT 0.000 26.583 0.024 26.607 ;
    END
  END wmask_in[33]
  PIN wmask_in[34]
    DIRECTION INPUT ;
    USE SIGNAL ;
    SHAPE ABUTMENT ;
    PORT
      LAYER M4 ;
      RECT 0.000 26.727 0.024 26.751 ;
    END
  END wmask_in[34]
  PIN wmask_in[35]
    DIRECTION INPUT ;
    USE SIGNAL ;
    SHAPE ABUTMENT ;
    PORT
      LAYER M4 ;
      RECT 0.000 26.871 0.024 26.895 ;
    END
  END wmask_in[35]
  PIN wmask_in[36]
    DIRECTION INPUT ;
    USE SIGNAL ;
    SHAPE ABUTMENT ;
    PORT
      LAYER M4 ;
      RECT 0.000 27.015 0.024 27.039 ;
    END
  END wmask_in[36]
  PIN wmask_in[37]
    DIRECTION INPUT ;
    USE SIGNAL ;
    SHAPE ABUTMENT ;
    PORT
      LAYER M4 ;
      RECT 0.000 27.159 0.024 27.183 ;
    END
  END wmask_in[37]
  PIN wmask_in[38]
    DIRECTION INPUT ;
    USE SIGNAL ;
    SHAPE ABUTMENT ;
    PORT
      LAYER M4 ;
      RECT 0.000 27.303 0.024 27.327 ;
    END
  END wmask_in[38]
  PIN wmask_in[39]
    DIRECTION INPUT ;
    USE SIGNAL ;
    SHAPE ABUTMENT ;
    PORT
      LAYER M4 ;
      RECT 0.000 27.447 0.024 27.471 ;
    END
  END wmask_in[39]
  PIN wmask_in[40]
    DIRECTION INPUT ;
    USE SIGNAL ;
    SHAPE ABUTMENT ;
    PORT
      LAYER M4 ;
      RECT 0.000 27.591 0.024 27.615 ;
    END
  END wmask_in[40]
  PIN wmask_in[41]
    DIRECTION INPUT ;
    USE SIGNAL ;
    SHAPE ABUTMENT ;
    PORT
      LAYER M4 ;
      RECT 0.000 27.735 0.024 27.759 ;
    END
  END wmask_in[41]
  PIN wmask_in[42]
    DIRECTION INPUT ;
    USE SIGNAL ;
    SHAPE ABUTMENT ;
    PORT
      LAYER M4 ;
      RECT 0.000 27.879 0.024 27.903 ;
    END
  END wmask_in[42]
  PIN wmask_in[43]
    DIRECTION INPUT ;
    USE SIGNAL ;
    SHAPE ABUTMENT ;
    PORT
      LAYER M4 ;
      RECT 0.000 28.023 0.024 28.047 ;
    END
  END wmask_in[43]
  PIN wmask_in[44]
    DIRECTION INPUT ;
    USE SIGNAL ;
    SHAPE ABUTMENT ;
    PORT
      LAYER M4 ;
      RECT 0.000 28.167 0.024 28.191 ;
    END
  END wmask_in[44]
  PIN wmask_in[45]
    DIRECTION INPUT ;
    USE SIGNAL ;
    SHAPE ABUTMENT ;
    PORT
      LAYER M4 ;
      RECT 0.000 28.311 0.024 28.335 ;
    END
  END wmask_in[45]
  PIN wmask_in[46]
    DIRECTION INPUT ;
    USE SIGNAL ;
    SHAPE ABUTMENT ;
    PORT
      LAYER M4 ;
      RECT 0.000 28.455 0.024 28.479 ;
    END
  END wmask_in[46]
  PIN wmask_in[47]
    DIRECTION INPUT ;
    USE SIGNAL ;
    SHAPE ABUTMENT ;
    PORT
      LAYER M4 ;
      RECT 0.000 28.599 0.024 28.623 ;
    END
  END wmask_in[47]
  PIN wmask_in[48]
    DIRECTION INPUT ;
    USE SIGNAL ;
    SHAPE ABUTMENT ;
    PORT
      LAYER M4 ;
      RECT 0.000 28.743 0.024 28.767 ;
    END
  END wmask_in[48]
  PIN wmask_in[49]
    DIRECTION INPUT ;
    USE SIGNAL ;
    SHAPE ABUTMENT ;
    PORT
      LAYER M4 ;
      RECT 0.000 28.887 0.024 28.911 ;
    END
  END wmask_in[49]
  PIN wmask_in[50]
    DIRECTION INPUT ;
    USE SIGNAL ;
    SHAPE ABUTMENT ;
    PORT
      LAYER M4 ;
      RECT 0.000 29.031 0.024 29.055 ;
    END
  END wmask_in[50]
  PIN wmask_in[51]
    DIRECTION INPUT ;
    USE SIGNAL ;
    SHAPE ABUTMENT ;
    PORT
      LAYER M4 ;
      RECT 0.000 29.175 0.024 29.199 ;
    END
  END wmask_in[51]
  PIN wmask_in[52]
    DIRECTION INPUT ;
    USE SIGNAL ;
    SHAPE ABUTMENT ;
    PORT
      LAYER M4 ;
      RECT 0.000 29.319 0.024 29.343 ;
    END
  END wmask_in[52]
  PIN wmask_in[53]
    DIRECTION INPUT ;
    USE SIGNAL ;
    SHAPE ABUTMENT ;
    PORT
      LAYER M4 ;
      RECT 0.000 29.463 0.024 29.487 ;
    END
  END wmask_in[53]
  PIN wmask_in[54]
    DIRECTION INPUT ;
    USE SIGNAL ;
    SHAPE ABUTMENT ;
    PORT
      LAYER M4 ;
      RECT 0.000 29.607 0.024 29.631 ;
    END
  END wmask_in[54]
  PIN wmask_in[55]
    DIRECTION INPUT ;
    USE SIGNAL ;
    SHAPE ABUTMENT ;
    PORT
      LAYER M4 ;
      RECT 0.000 29.751 0.024 29.775 ;
    END
  END wmask_in[55]
  PIN wmask_in[56]
    DIRECTION INPUT ;
    USE SIGNAL ;
    SHAPE ABUTMENT ;
    PORT
      LAYER M4 ;
      RECT 0.000 29.895 0.024 29.919 ;
    END
  END wmask_in[56]
  PIN wmask_in[57]
    DIRECTION INPUT ;
    USE SIGNAL ;
    SHAPE ABUTMENT ;
    PORT
      LAYER M4 ;
      RECT 0.000 30.039 0.024 30.063 ;
    END
  END wmask_in[57]
  PIN wmask_in[58]
    DIRECTION INPUT ;
    USE SIGNAL ;
    SHAPE ABUTMENT ;
    PORT
      LAYER M4 ;
      RECT 0.000 30.183 0.024 30.207 ;
    END
  END wmask_in[58]
  PIN wmask_in[59]
    DIRECTION INPUT ;
    USE SIGNAL ;
    SHAPE ABUTMENT ;
    PORT
      LAYER M4 ;
      RECT 0.000 30.327 0.024 30.351 ;
    END
  END wmask_in[59]
  PIN wmask_in[60]
    DIRECTION INPUT ;
    USE SIGNAL ;
    SHAPE ABUTMENT ;
    PORT
      LAYER M4 ;
      RECT 0.000 30.471 0.024 30.495 ;
    END
  END wmask_in[60]
  PIN wmask_in[61]
    DIRECTION INPUT ;
    USE SIGNAL ;
    SHAPE ABUTMENT ;
    PORT
      LAYER M4 ;
      RECT 0.000 30.615 0.024 30.639 ;
    END
  END wmask_in[61]
  PIN wmask_in[62]
    DIRECTION INPUT ;
    USE SIGNAL ;
    SHAPE ABUTMENT ;
    PORT
      LAYER M4 ;
      RECT 0.000 30.759 0.024 30.783 ;
    END
  END wmask_in[62]
  PIN wmask_in[63]
    DIRECTION INPUT ;
    USE SIGNAL ;
    SHAPE ABUTMENT ;
    PORT
      LAYER M4 ;
      RECT 0.000 30.903 0.024 30.927 ;
    END
  END wmask_in[63]
  PIN wen_in
    DIRECTION INPUT ;
    USE SIGNAL ;
    SHAPE ABUTMENT ;
    PORT
      LAYER M4 ;
      RECT 0.000 31.383 0.024 31.407 ;
    END
  END wen_in
  PIN ren_in
    DIRECTION INPUT ;
    USE SIGNAL ;
    SHAPE ABUTMENT ;
    PORT
      LAYER M4 ;
      RECT 0.000 31.527 0.024 31.551 ;
    END
  END ren_in
  PIN wclk
    DIRECTION INPUT ;
    USE SIGNAL ;
    SHAPE ABUTMENT ;
    PORT
      LAYER M4 ;
      RECT 0.000 31.671 0.024 31.695 ;
    END
  END wclk
  PIN rclk
    DIRECTION INPUT ;
    USE SIGNAL ;
    SHAPE ABUTMENT ;
    PORT
      LAYER M4 ;
      RECT 0.000 31.815 0.024 31.839 ;
    END
  END rclk
  PIN VSS
    DIRECTION INOUT ;
    USE GROUND ;
    PORT
      LAYER M4 ;
      RECT 0.048 0.000 8.312 0.096 ;
      RECT 0.048 0.768 8.312 0.864 ;
      RECT 0.048 1.536 8.312 1.632 ;
      RECT 0.048 2.304 8.312 2.400 ;
      RECT 0.048 3.072 8.312 3.168 ;
      RECT 0.048 3.840 8.312 3.936 ;
      RECT 0.048 4.608 8.312 4.704 ;
      RECT 0.048 5.376 8.312 5.472 ;
      RECT 0.048 6.144 8.312 6.240 ;
      RECT 0.048 6.912 8.312 7.008 ;
      RECT 0.048 7.680 8.312 7.776 ;
      RECT 0.048 8.448 8.312 8.544 ;
      RECT 0.048 9.216 8.312 9.312 ;
      RECT 0.048 9.984 8.312 10.080 ;
      RECT 0.048 10.752 8.312 10.848 ;
      RECT 0.048 11.520 8.312 11.616 ;
      RECT 0.048 12.288 8.312 12.384 ;
      RECT 0.048 13.056 8.312 13.152 ;
      RECT 0.048 13.824 8.312 13.920 ;
      RECT 0.048 14.592 8.312 14.688 ;
      RECT 0.048 15.360 8.312 15.456 ;
      RECT 0.048 16.128 8.312 16.224 ;
      RECT 0.048 16.896 8.312 16.992 ;
      RECT 0.048 17.664 8.312 17.760 ;
      RECT 0.048 18.432 8.312 18.528 ;
      RECT 0.048 19.200 8.312 19.296 ;
      RECT 0.048 19.968 8.312 20.064 ;
      RECT 0.048 20.736 8.312 20.832 ;
      RECT 0.048 21.504 8.312 21.600 ;
      RECT 0.048 22.272 8.312 22.368 ;
      RECT 0.048 23.040 8.312 23.136 ;
      RECT 0.048 23.808 8.312 23.904 ;
      RECT 0.048 24.576 8.312 24.672 ;
      RECT 0.048 25.344 8.312 25.440 ;
      RECT 0.048 26.112 8.312 26.208 ;
      RECT 0.048 26.880 8.312 26.976 ;
      RECT 0.048 27.648 8.312 27.744 ;
      RECT 0.048 28.416 8.312 28.512 ;
      RECT 0.048 29.184 8.312 29.280 ;
      RECT 0.048 29.952 8.312 30.048 ;
      RECT 0.048 30.720 8.312 30.816 ;
      RECT 0.048 31.488 8.312 31.584 ;
      RECT 0.048 32.256 8.312 32.352 ;
      RECT 0.048 33.024 8.312 33.120 ;
    END
  END VSS
  PIN VDD
    DIRECTION INOUT ;
    USE POWER ;
    PORT
      LAYER M4 ;
      RECT 0.048 0.384 8.312 0.480 ;
      RECT 0.048 1.152 8.312 1.248 ;
      RECT 0.048 1.920 8.312 2.016 ;
      RECT 0.048 2.688 8.312 2.784 ;
      RECT 0.048 3.456 8.312 3.552 ;
      RECT 0.048 4.224 8.312 4.320 ;
      RECT 0.048 4.992 8.312 5.088 ;
      RECT 0.048 5.760 8.312 5.856 ;
      RECT 0.048 6.528 8.312 6.624 ;
      RECT 0.048 7.296 8.312 7.392 ;
      RECT 0.048 8.064 8.312 8.160 ;
      RECT 0.048 8.832 8.312 8.928 ;
      RECT 0.048 9.600 8.312 9.696 ;
      RECT 0.048 10.368 8.312 10.464 ;
      RECT 0.048 11.136 8.312 11.232 ;
      RECT 0.048 11.904 8.312 12.000 ;
      RECT 0.048 12.672 8.312 12.768 ;
      RECT 0.048 13.440 8.312 13.536 ;
      RECT 0.048 14.208 8.312 14.304 ;
      RECT 0.048 14.976 8.312 15.072 ;
      RECT 0.048 15.744 8.312 15.840 ;
      RECT 0.048 16.512 8.312 16.608 ;
      RECT 0.048 17.280 8.312 17.376 ;
      RECT 0.048 18.048 8.312 18.144 ;
      RECT 0.048 18.816 8.312 18.912 ;
      RECT 0.048 19.584 8.312 19.680 ;
      RECT 0.048 20.352 8.312 20.448 ;
      RECT 0.048 21.120 8.312 21.216 ;
      RECT 0.048 21.888 8.312 21.984 ;
      RECT 0.048 22.656 8.312 22.752 ;
      RECT 0.048 23.424 8.312 23.520 ;
      RECT 0.048 24.192 8.312 24.288 ;
      RECT 0.048 24.960 8.312 25.056 ;
      RECT 0.048 25.728 8.312 25.824 ;
      RECT 0.048 26.496 8.312 26.592 ;
      RECT 0.048 27.264 8.312 27.360 ;
      RECT 0.048 28.032 8.312 28.128 ;
      RECT 0.048 28.800 8.312 28.896 ;
      RECT 0.048 29.568 8.312 29.664 ;
      RECT 0.048 30.336 8.312 30.432 ;
      RECT 0.048 31.104 8.312 31.200 ;
      RECT 0.048 31.872 8.312 31.968 ;
      RECT 0.048 32.640 8.312 32.736 ;
      RECT 0.048 33.408 8.312 33.504 ;
    END
  END VDD
  OBS
    LAYER M1 ;
    RECT 0 0 8.360 33.600 ;
    LAYER M2 ;
    RECT 0 0 8.360 33.600 ;
    LAYER M3 ;
    RECT 0.059 0.000 8.360 33.600 ;
    LAYER M4 ;
    RECT 0.100 0.000 8.260 33.600 ;
  END
END fakeregfile_128x64_bottom

END LIBRARY
